VERSION 5.7 ;
  NOWIREEXTENSIONATPIN ON ;
  DIVIDERCHAR "/" ;
  BUSBITCHARS "[]" ;
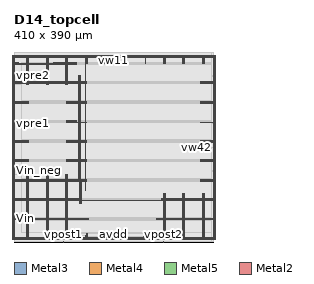
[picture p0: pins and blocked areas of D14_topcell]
MACRO D14_topcell
  CLASS BLOCK ;
  FOREIGN D14_topcell ;
  ORIGIN 0.000 0.000 ;
  SIZE 410.000 BY 390.000 ;
  PIN Vin
    DIRECTION INPUT ;
    USE SIGNAL ;
    ANTENNAGATEAREA 5.000000 ;
    PORT
      LAYER Metal3 ;
        RECT 0.000 48.160 0.560 48.720 ;
    END
  END Vin
  PIN Vin_neg
    DIRECTION INPUT ;
    USE SIGNAL ;
    ANTENNAGATEAREA 5.000000 ;
    PORT
      LAYER Metal3 ;
        RECT 0.000 145.600 0.560 146.160 ;
    END
  END Vin_neg
  PIN avdd
    DIRECTION INOUT ;
    USE POWER ;
    PORT
      LAYER Metal4 ;
        RECT -0.780 8.180 0.720 379.900 ;
    END
    PORT
      LAYER Metal4 ;
        RECT 409.200 8.180 410.700 379.900 ;
    END
    PORT
      LAYER Metal5 ;
        RECT -0.780 8.180 410.700 9.680 ;
    END
    PORT
      LAYER Metal5 ;
        RECT -0.780 378.400 410.700 379.900 ;
    END
    PORT
      LAYER Metal4 ;
        RECT 26.220 5.180 27.220 138.130 ;
    END
    PORT
      LAYER Metal4 ;
        RECT 26.220 323.710 27.220 382.900 ;
    END
    PORT
      LAYER Metal4 ;
        RECT 66.220 5.180 67.220 138.130 ;
    END
    PORT
      LAYER Metal4 ;
        RECT 66.220 323.710 67.220 382.900 ;
    END
    PORT
      LAYER Metal4 ;
        RECT 106.220 5.180 107.220 138.130 ;
    END
    PORT
      LAYER Metal4 ;
        RECT 106.220 323.710 107.220 382.900 ;
    END
    PORT
      LAYER Metal4 ;
        RECT 146.220 5.180 147.220 13.620 ;
    END
    PORT
      LAYER Metal4 ;
        RECT 146.220 104.780 147.220 382.900 ;
    END
    PORT
      LAYER Metal4 ;
        RECT 186.220 5.180 187.220 10.930 ;
    END
    PORT
      LAYER Metal4 ;
        RECT 186.220 365.385 187.220 382.900 ;
    END
    PORT
      LAYER Metal4 ;
        RECT 226.220 5.180 227.220 10.930 ;
    END
    PORT
      LAYER Metal4 ;
        RECT 226.220 365.385 227.220 382.900 ;
    END
    PORT
      LAYER Metal4 ;
        RECT 266.220 5.180 267.220 10.930 ;
    END
    PORT
      LAYER Metal4 ;
        RECT 266.220 379.020 267.220 382.900 ;
    END
    PORT
      LAYER Metal4 ;
        RECT 306.220 5.180 307.220 99.810 ;
    END
    PORT
      LAYER Metal4 ;
        RECT 306.220 365.385 307.220 382.900 ;
    END
    PORT
      LAYER Metal4 ;
        RECT 346.220 5.180 347.220 99.810 ;
    END
    PORT
      LAYER Metal4 ;
        RECT 346.220 365.385 347.220 382.900 ;
    END
    PORT
      LAYER Metal4 ;
        RECT 386.220 5.180 387.220 99.810 ;
    END
    PORT
      LAYER Metal4 ;
        RECT 386.220 365.385 387.220 382.900 ;
    END
    PORT
      LAYER Metal5 ;
        RECT -3.780 45.180 152.540 46.180 ;
    END
    PORT
      LAYER Metal5 ;
        RECT -3.780 85.180 413.700 86.180 ;
    END
    PORT
      LAYER Metal5 ;
        RECT -3.780 125.180 149.540 126.180 ;
    END
    PORT
      LAYER Metal5 ;
        RECT -3.780 165.180 29.540 166.180 ;
    END
    PORT
      LAYER Metal5 ;
        RECT -3.780 205.180 29.540 206.180 ;
    END
    PORT
      LAYER Metal5 ;
        RECT -3.780 245.180 29.540 246.180 ;
    END
    PORT
      LAYER Metal5 ;
        RECT -3.780 285.180 29.540 286.180 ;
    END
    PORT
      LAYER Metal5 ;
        RECT -3.780 325.180 149.540 326.180 ;
    END
    PORT
      LAYER Metal5 ;
        RECT -3.780 365.180 128.700 366.180 ;
    END
    PORT
      LAYER Metal5 ;
        RECT 108.320 165.180 149.540 166.180 ;
    END
    PORT
      LAYER Metal5 ;
        RECT 108.320 205.180 149.540 206.180 ;
    END
    PORT
      LAYER Metal5 ;
        RECT 108.320 245.180 149.540 246.180 ;
    END
    PORT
      LAYER Metal5 ;
        RECT 108.320 285.180 149.540 286.180 ;
    END
    PORT
      LAYER Metal5 ;
        RECT 293.320 45.180 413.700 46.180 ;
    END
    PORT
      LAYER Metal5 ;
        RECT 382.440 125.180 413.700 126.180 ;
    END
    PORT
      LAYER Metal5 ;
        RECT 382.440 165.180 413.700 166.180 ;
    END
    PORT
      LAYER Metal5 ;
        RECT 382.440 205.180 413.700 206.180 ;
    END
    PORT
      LAYER Metal5 ;
        RECT 382.440 245.180 413.700 246.180 ;
    END
    PORT
      LAYER Metal5 ;
        RECT 382.440 285.180 413.700 286.180 ;
    END
    PORT
      LAYER Metal5 ;
        RECT 382.440 325.180 413.700 326.180 ;
    END
    PORT
      LAYER Metal4 ;
        RECT 133.060 129.060 134.060 341.340 ;
    END
    PORT
      LAYER Metal4 ;
        RECT 133.620 78.100 134.620 128.780 ;
    END
  END avdd
  PIN avss
    DIRECTION INOUT ;
    USE GROUND ;
    PORT
      LAYER Metal4 ;
        RECT -3.780 5.180 -2.280 382.900 ;
    END
    PORT
      LAYER Metal4 ;
        RECT 412.200 5.180 413.700 382.900 ;
    END
    PORT
      LAYER Metal5 ;
        RECT -3.780 5.180 413.700 6.680 ;
    END
    PORT
      LAYER Metal5 ;
        RECT -3.780 381.400 413.700 382.900 ;
    END
    PORT
      LAYER Metal4 ;
        RECT 29.220 5.180 30.220 138.130 ;
    END
    PORT
      LAYER Metal4 ;
        RECT 29.220 323.710 30.220 382.900 ;
    END
    PORT
      LAYER Metal4 ;
        RECT 69.220 5.180 70.220 138.130 ;
    END
    PORT
      LAYER Metal4 ;
        RECT 69.220 323.710 70.220 382.900 ;
    END
    PORT
      LAYER Metal4 ;
        RECT 109.220 5.180 110.220 138.130 ;
    END
    PORT
      LAYER Metal4 ;
        RECT 109.220 323.710 110.220 382.900 ;
    END
    PORT
      LAYER Metal4 ;
        RECT 149.220 5.180 150.220 17.120 ;
    END
    PORT
      LAYER Metal4 ;
        RECT 149.220 365.385 150.220 382.900 ;
    END
    PORT
      LAYER Metal4 ;
        RECT 189.220 5.180 190.220 10.930 ;
    END
    PORT
      LAYER Metal4 ;
        RECT 189.220 365.385 190.220 382.900 ;
    END
    PORT
      LAYER Metal4 ;
        RECT 229.220 5.180 230.220 10.930 ;
    END
    PORT
      LAYER Metal4 ;
        RECT 229.220 365.385 230.220 382.900 ;
    END
    PORT
      LAYER Metal4 ;
        RECT 269.220 5.180 270.220 10.930 ;
    END
    PORT
      LAYER Metal4 ;
        RECT 269.220 365.385 270.220 382.900 ;
    END
    PORT
      LAYER Metal4 ;
        RECT 309.220 5.180 310.220 99.810 ;
    END
    PORT
      LAYER Metal4 ;
        RECT 309.220 365.385 310.220 382.900 ;
    END
    PORT
      LAYER Metal4 ;
        RECT 349.220 5.180 350.220 99.810 ;
    END
    PORT
      LAYER Metal4 ;
        RECT 349.220 365.385 350.220 382.900 ;
    END
    PORT
      LAYER Metal4 ;
        RECT 389.220 5.180 390.220 99.810 ;
    END
    PORT
      LAYER Metal4 ;
        RECT 389.220 365.385 390.220 382.900 ;
    END
    PORT
      LAYER Metal5 ;
        RECT -3.780 48.180 152.540 49.180 ;
    END
    PORT
      LAYER Metal5 ;
        RECT -3.780 88.180 137.800 89.180 ;
    END
    PORT
      LAYER Metal5 ;
        RECT -3.780 128.180 149.540 129.180 ;
    END
    PORT
      LAYER Metal5 ;
        RECT -3.780 168.180 29.540 169.180 ;
    END
    PORT
      LAYER Metal5 ;
        RECT -3.780 208.180 29.540 209.180 ;
    END
    PORT
      LAYER Metal5 ;
        RECT -3.780 248.180 29.540 249.180 ;
    END
    PORT
      LAYER Metal5 ;
        RECT -3.780 288.180 29.540 289.180 ;
    END
    PORT
      LAYER Metal5 ;
        RECT -3.780 328.180 149.540 329.180 ;
    END
    PORT
      LAYER Metal5 ;
        RECT -3.780 368.180 9.080 369.180 ;
    END
    PORT
      LAYER Metal5 ;
        RECT 81.920 368.180 128.700 369.180 ;
    END
    PORT
      LAYER Metal5 ;
        RECT 108.320 168.180 149.540 169.180 ;
    END
    PORT
      LAYER Metal5 ;
        RECT 108.320 208.180 149.540 209.180 ;
    END
    PORT
      LAYER Metal5 ;
        RECT 108.320 248.180 128.700 249.180 ;
    END
    PORT
      LAYER Metal5 ;
        RECT 108.320 288.180 149.540 289.180 ;
    END
    PORT
      LAYER Metal5 ;
        RECT 293.320 48.180 413.700 49.180 ;
    END
    PORT
      LAYER Metal5 ;
        RECT 302.200 88.180 413.700 89.180 ;
    END
    PORT
      LAYER Metal5 ;
        RECT 382.440 128.180 413.700 129.180 ;
    END
    PORT
      LAYER Metal5 ;
        RECT 382.440 168.180 413.700 169.180 ;
    END
    PORT
      LAYER Metal5 ;
        RECT 382.440 208.180 413.700 209.180 ;
    END
    PORT
      LAYER Metal5 ;
        RECT 382.440 288.180 413.700 289.180 ;
    END
    PORT
      LAYER Metal5 ;
        RECT 382.440 328.180 413.700 329.180 ;
    END
    PORT
      LAYER Metal4 ;
        RECT 136.420 129.060 137.420 341.340 ;
    END
    PORT
      LAYER Metal4 ;
        RECT 136.980 78.100 137.980 128.780 ;
    END
  END avss
  PIN vpost1
    DIRECTION OUTPUT ;
    USE SIGNAL ;
    ANTENNAGATEAREA 1.260000 ;
    ANTENNADIFFAREA 0.750000 ;
    PORT
      LAYER Metal2 ;
        RECT 101.920 0.000 102.480 0.560 ;
    END
  END vpost1
  PIN vpost2
    DIRECTION OUTPUT ;
    USE SIGNAL ;
    ANTENNAGATEAREA 1.260000 ;
    ANTENNADIFFAREA 0.750000 ;
    PORT
      LAYER Metal2 ;
        RECT 306.880 0.000 307.440 0.560 ;
    END
  END vpost2
  PIN vpre1
    DIRECTION OUTPUT ;
    USE SIGNAL ;
    ANTENNADIFFAREA 0.750000 ;
    PORT
      LAYER Metal3 ;
        RECT 0.000 243.040 0.560 243.600 ;
    END
  END vpre1
  PIN vpre2
    DIRECTION OUTPUT ;
    USE SIGNAL ;
    ANTENNADIFFAREA 0.750000 ;
    PORT
      LAYER Metal3 ;
        RECT 0.000 340.480 0.560 341.040 ;
    END
  END vpre2
  PIN vw11
    DIRECTION OUTPUT ;
    USE SIGNAL ;
    ANTENNAGATEAREA 78.815201 ;
    ANTENNADIFFAREA 542.857971 ;
    PORT
      LAYER Metal2 ;
        RECT 203.840 389.440 204.400 390.000 ;
    END
  END vw11
  PIN vw42
    DIRECTION OUTPUT ;
    USE SIGNAL ;
    ANTENNAGATEAREA 78.815201 ;
    ANTENNADIFFAREA 542.857971 ;
    PORT
      LAYER Metal3 ;
        RECT 409.440 193.760 410.000 194.320 ;
    END
  END vw42
  OBS
      LAYER Nwell ;
        RECT 22.000 38.300 364.810 364.235 ;
      LAYER Metal1 ;
        RECT 6.720 15.380 403.200 372.700 ;
      LAYER Metal2 ;
        RECT 20.900 15.490 390.120 372.590 ;
      LAYER Metal3 ;
        RECT 0.560 341.340 409.440 389.860 ;
        RECT 0.860 340.180 409.440 341.340 ;
        RECT 0.560 243.900 409.440 340.180 ;
        RECT 0.860 242.740 409.440 243.900 ;
        RECT 0.560 194.620 409.440 242.740 ;
        RECT 0.560 193.460 409.140 194.620 ;
        RECT 0.560 146.460 409.440 193.460 ;
        RECT 0.860 145.300 409.440 146.460 ;
        RECT 0.560 49.020 409.440 145.300 ;
        RECT 0.860 47.860 409.440 49.020 ;
        RECT 0.560 0.140 409.440 47.860 ;
      LAYER Metal4 ;
        RECT 1.260 383.200 405.100 389.670 ;
        RECT 1.260 323.410 25.920 383.200 ;
        RECT 27.520 323.410 28.920 383.200 ;
        RECT 30.520 323.410 65.920 383.200 ;
        RECT 67.520 323.410 68.920 383.200 ;
        RECT 70.520 323.410 105.920 383.200 ;
        RECT 107.520 323.410 108.920 383.200 ;
        RECT 110.520 341.640 145.920 383.200 ;
        RECT 110.520 323.410 132.760 341.640 ;
        RECT 1.260 138.430 132.760 323.410 ;
        RECT 1.260 4.880 25.920 138.430 ;
        RECT 27.520 4.880 28.920 138.430 ;
        RECT 30.520 4.880 65.920 138.430 ;
        RECT 67.520 4.880 68.920 138.430 ;
        RECT 70.520 4.880 105.920 138.430 ;
        RECT 107.520 4.880 108.920 138.430 ;
        RECT 110.520 128.760 132.760 138.430 ;
        RECT 134.360 129.080 136.120 341.640 ;
        RECT 137.720 129.080 145.920 341.640 ;
        RECT 134.920 128.760 136.120 129.080 ;
        RECT 110.520 77.800 133.320 128.760 ;
        RECT 134.920 77.800 136.680 128.760 ;
        RECT 138.280 104.480 145.920 129.080 ;
        RECT 147.520 365.085 148.920 383.200 ;
        RECT 150.520 365.085 185.920 383.200 ;
        RECT 187.520 365.085 188.920 383.200 ;
        RECT 190.520 365.085 225.920 383.200 ;
        RECT 227.520 365.085 228.920 383.200 ;
        RECT 230.520 378.720 265.920 383.200 ;
        RECT 267.520 378.720 268.920 383.200 ;
        RECT 230.520 365.085 268.920 378.720 ;
        RECT 270.520 365.085 305.920 383.200 ;
        RECT 307.520 365.085 308.920 383.200 ;
        RECT 310.520 365.085 345.920 383.200 ;
        RECT 347.520 365.085 348.920 383.200 ;
        RECT 350.520 365.085 385.920 383.200 ;
        RECT 387.520 365.085 388.920 383.200 ;
        RECT 390.520 365.085 405.100 383.200 ;
        RECT 147.520 104.480 405.100 365.085 ;
        RECT 138.280 100.110 405.100 104.480 ;
        RECT 138.280 77.800 305.920 100.110 ;
        RECT 110.520 17.420 305.920 77.800 ;
        RECT 110.520 13.920 148.920 17.420 ;
        RECT 110.520 4.880 145.920 13.920 ;
        RECT 147.520 4.880 148.920 13.920 ;
        RECT 150.520 11.230 305.920 17.420 ;
        RECT 150.520 4.880 185.920 11.230 ;
        RECT 187.520 4.880 188.920 11.230 ;
        RECT 190.520 4.880 225.920 11.230 ;
        RECT 227.520 4.880 228.920 11.230 ;
        RECT 230.520 4.880 265.920 11.230 ;
        RECT 267.520 4.880 268.920 11.230 ;
        RECT 270.520 4.880 305.920 11.230 ;
        RECT 307.520 4.880 308.920 100.110 ;
        RECT 310.520 4.880 345.920 100.110 ;
        RECT 347.520 4.880 348.920 100.110 ;
        RECT 350.520 4.880 385.920 100.110 ;
        RECT 387.520 4.880 388.920 100.110 ;
        RECT 390.520 4.880 405.100 100.110 ;
        RECT 1.260 0.090 405.100 4.880 ;
      LAYER Metal5 ;
        RECT 16.220 367.580 81.320 368.460 ;
        RECT 129.300 367.580 405.100 368.460 ;
        RECT 16.220 366.780 405.100 367.580 ;
        RECT 129.300 364.580 405.100 366.780 ;
        RECT 16.220 329.780 405.100 364.580 ;
        RECT 150.140 327.580 381.840 329.780 ;
        RECT 16.220 326.780 405.100 327.580 ;
        RECT 150.140 324.580 381.840 326.780 ;
        RECT 16.220 289.780 405.100 324.580 ;
        RECT 30.140 287.580 107.720 289.780 ;
        RECT 150.140 287.580 381.840 289.780 ;
        RECT 16.220 286.780 405.100 287.580 ;
        RECT 30.140 284.580 107.720 286.780 ;
        RECT 150.140 284.580 381.840 286.780 ;
        RECT 16.220 249.780 405.100 284.580 ;
        RECT 30.140 247.580 107.720 249.780 ;
        RECT 129.300 247.580 405.100 249.780 ;
        RECT 16.220 246.780 405.100 247.580 ;
        RECT 30.140 244.580 107.720 246.780 ;
        RECT 150.140 244.580 381.840 246.780 ;
        RECT 16.220 209.780 405.100 244.580 ;
        RECT 30.140 207.580 107.720 209.780 ;
        RECT 150.140 207.580 381.840 209.780 ;
        RECT 16.220 206.780 405.100 207.580 ;
        RECT 30.140 204.580 107.720 206.780 ;
        RECT 150.140 204.580 381.840 206.780 ;
        RECT 16.220 169.780 405.100 204.580 ;
        RECT 30.140 167.580 107.720 169.780 ;
        RECT 150.140 167.580 381.840 169.780 ;
        RECT 16.220 166.780 405.100 167.580 ;
        RECT 30.140 164.580 107.720 166.780 ;
        RECT 150.140 164.580 381.840 166.780 ;
        RECT 16.220 129.780 405.100 164.580 ;
        RECT 150.140 127.580 381.840 129.780 ;
        RECT 16.220 126.780 405.100 127.580 ;
        RECT 150.140 124.580 381.840 126.780 ;
        RECT 16.220 89.780 405.100 124.580 ;
        RECT 138.400 87.580 301.600 89.780 ;
        RECT 16.220 86.780 405.100 87.580 ;
        RECT 16.220 49.780 405.100 84.580 ;
        RECT 153.140 47.580 292.720 49.780 ;
        RECT 16.220 46.780 405.100 47.580 ;
        RECT 153.140 44.580 292.720 46.780 ;
        RECT 16.220 19.130 405.100 44.580 ;
  END
END D14_topcell
END LIBRARY

